# Generated by FakeRAM 2.0
VERSION 5.7 ;
BUSBITCHARS "[]" ;
PROPERTYDEFINITIONS
  MACRO width INTEGER ;
  MACRO depth INTEGER ;
  MACRO banks INTEGER ;
END PROPERTYDEFINITIONS
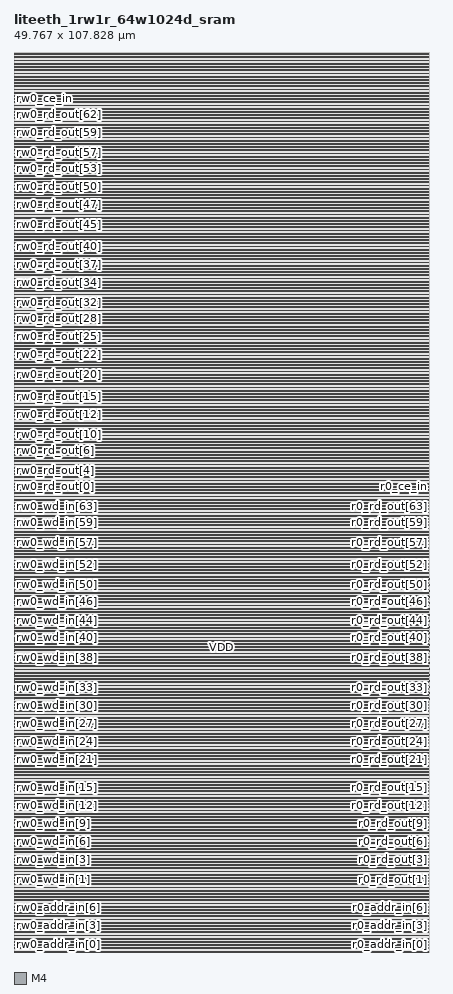
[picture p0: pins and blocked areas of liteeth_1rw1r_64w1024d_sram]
MACRO liteeth_1rw1r_64w1024d_sram
  PROPERTY width 64 ;
  PROPERTY depth 1024 ;
  PROPERTY banks 1 ;
  FOREIGN liteeth_1rw1r_64w1024d_sram 0 0 ;
  SYMMETRY X Y R90 ;
  SIZE 49.767 BY 107.828 ;
  CLASS BLOCK ;
  PIN r0_addr_in[0]
    DIRECTION INPUT ;
    USE SIGNAL ;
    SHAPE ABUTMENT ;
    PORT
      LAYER M4 ;
      RECT 49.743 0.048 49.767 0.072 ;
    END
  END r0_addr_in[0]
  PIN r0_addr_in[1]
    DIRECTION INPUT ;
    USE SIGNAL ;
    SHAPE ABUTMENT ;
    PORT
      LAYER M4 ;
      RECT 49.743 0.768 49.767 0.792 ;
    END
  END r0_addr_in[1]
  PIN r0_addr_in[2]
    DIRECTION INPUT ;
    USE SIGNAL ;
    SHAPE ABUTMENT ;
    PORT
      LAYER M4 ;
      RECT 49.743 1.488 49.767 1.512 ;
    END
  END r0_addr_in[2]
  PIN r0_addr_in[3]
    DIRECTION INPUT ;
    USE SIGNAL ;
    SHAPE ABUTMENT ;
    PORT
      LAYER M4 ;
      RECT 49.743 2.208 49.767 2.232 ;
    END
  END r0_addr_in[3]
  PIN r0_addr_in[4]
    DIRECTION INPUT ;
    USE SIGNAL ;
    SHAPE ABUTMENT ;
    PORT
      LAYER M4 ;
      RECT 49.743 2.928 49.767 2.952 ;
    END
  END r0_addr_in[4]
  PIN r0_addr_in[5]
    DIRECTION INPUT ;
    USE SIGNAL ;
    SHAPE ABUTMENT ;
    PORT
      LAYER M4 ;
      RECT 49.743 3.648 49.767 3.672 ;
    END
  END r0_addr_in[5]
  PIN r0_addr_in[6]
    DIRECTION INPUT ;
    USE SIGNAL ;
    SHAPE ABUTMENT ;
    PORT
      LAYER M4 ;
      RECT 49.743 4.368 49.767 4.392 ;
    END
  END r0_addr_in[6]
  PIN r0_addr_in[7]
    DIRECTION INPUT ;
    USE SIGNAL ;
    SHAPE ABUTMENT ;
    PORT
      LAYER M4 ;
      RECT 49.743 5.088 49.767 5.112 ;
    END
  END r0_addr_in[7]
  PIN r0_addr_in[8]
    DIRECTION INPUT ;
    USE SIGNAL ;
    SHAPE ABUTMENT ;
    PORT
      LAYER M4 ;
      RECT 49.743 5.808 49.767 5.832 ;
    END
  END r0_addr_in[8]
  PIN r0_addr_in[9]
    DIRECTION INPUT ;
    USE SIGNAL ;
    SHAPE ABUTMENT ;
    PORT
      LAYER M4 ;
      RECT 49.743 6.528 49.767 6.552 ;
    END
  END r0_addr_in[9]
  PIN r0_rd_out[0]
    DIRECTION OUTPUT ;
    USE SIGNAL ;
    SHAPE ABUTMENT ;
    PORT
      LAYER M4 ;
      RECT 49.743 7.968 49.767 7.992 ;
    END
  END r0_rd_out[0]
  PIN r0_rd_out[1]
    DIRECTION OUTPUT ;
    USE SIGNAL ;
    SHAPE ABUTMENT ;
    PORT
      LAYER M4 ;
      RECT 49.743 8.688 49.767 8.712 ;
    END
  END r0_rd_out[1]
  PIN r0_rd_out[2]
    DIRECTION OUTPUT ;
    USE SIGNAL ;
    SHAPE ABUTMENT ;
    PORT
      LAYER M4 ;
      RECT 49.743 9.408 49.767 9.432 ;
    END
  END r0_rd_out[2]
  PIN r0_rd_out[3]
    DIRECTION OUTPUT ;
    USE SIGNAL ;
    SHAPE ABUTMENT ;
    PORT
      LAYER M4 ;
      RECT 49.743 10.128 49.767 10.152 ;
    END
  END r0_rd_out[3]
  PIN r0_rd_out[4]
    DIRECTION OUTPUT ;
    USE SIGNAL ;
    SHAPE ABUTMENT ;
    PORT
      LAYER M4 ;
      RECT 49.743 10.848 49.767 10.872 ;
    END
  END r0_rd_out[4]
  PIN r0_rd_out[5]
    DIRECTION OUTPUT ;
    USE SIGNAL ;
    SHAPE ABUTMENT ;
    PORT
      LAYER M4 ;
      RECT 49.743 11.568 49.767 11.592 ;
    END
  END r0_rd_out[5]
  PIN r0_rd_out[6]
    DIRECTION OUTPUT ;
    USE SIGNAL ;
    SHAPE ABUTMENT ;
    PORT
      LAYER M4 ;
      RECT 49.743 12.288 49.767 12.312 ;
    END
  END r0_rd_out[6]
  PIN r0_rd_out[7]
    DIRECTION OUTPUT ;
    USE SIGNAL ;
    SHAPE ABUTMENT ;
    PORT
      LAYER M4 ;
      RECT 49.743 13.008 49.767 13.032 ;
    END
  END r0_rd_out[7]
  PIN r0_rd_out[8]
    DIRECTION OUTPUT ;
    USE SIGNAL ;
    SHAPE ABUTMENT ;
    PORT
      LAYER M4 ;
      RECT 49.743 13.728 49.767 13.752 ;
    END
  END r0_rd_out[8]
  PIN r0_rd_out[9]
    DIRECTION OUTPUT ;
    USE SIGNAL ;
    SHAPE ABUTMENT ;
    PORT
      LAYER M4 ;
      RECT 49.743 14.448 49.767 14.472 ;
    END
  END r0_rd_out[9]
  PIN r0_rd_out[10]
    DIRECTION OUTPUT ;
    USE SIGNAL ;
    SHAPE ABUTMENT ;
    PORT
      LAYER M4 ;
      RECT 49.743 15.168 49.767 15.192 ;
    END
  END r0_rd_out[10]
  PIN r0_rd_out[11]
    DIRECTION OUTPUT ;
    USE SIGNAL ;
    SHAPE ABUTMENT ;
    PORT
      LAYER M4 ;
      RECT 49.743 15.888 49.767 15.912 ;
    END
  END r0_rd_out[11]
  PIN r0_rd_out[12]
    DIRECTION OUTPUT ;
    USE SIGNAL ;
    SHAPE ABUTMENT ;
    PORT
      LAYER M4 ;
      RECT 49.743 16.608 49.767 16.632 ;
    END
  END r0_rd_out[12]
  PIN r0_rd_out[13]
    DIRECTION OUTPUT ;
    USE SIGNAL ;
    SHAPE ABUTMENT ;
    PORT
      LAYER M4 ;
      RECT 49.743 17.328 49.767 17.352 ;
    END
  END r0_rd_out[13]
  PIN r0_rd_out[14]
    DIRECTION OUTPUT ;
    USE SIGNAL ;
    SHAPE ABUTMENT ;
    PORT
      LAYER M4 ;
      RECT 49.743 18.048 49.767 18.072 ;
    END
  END r0_rd_out[14]
  PIN r0_rd_out[15]
    DIRECTION OUTPUT ;
    USE SIGNAL ;
    SHAPE ABUTMENT ;
    PORT
      LAYER M4 ;
      RECT 49.743 18.768 49.767 18.792 ;
    END
  END r0_rd_out[15]
  PIN r0_rd_out[16]
    DIRECTION OUTPUT ;
    USE SIGNAL ;
    SHAPE ABUTMENT ;
    PORT
      LAYER M4 ;
      RECT 49.743 19.488 49.767 19.512 ;
    END
  END r0_rd_out[16]
  PIN r0_rd_out[17]
    DIRECTION OUTPUT ;
    USE SIGNAL ;
    SHAPE ABUTMENT ;
    PORT
      LAYER M4 ;
      RECT 49.743 20.208 49.767 20.232 ;
    END
  END r0_rd_out[17]
  PIN r0_rd_out[18]
    DIRECTION OUTPUT ;
    USE SIGNAL ;
    SHAPE ABUTMENT ;
    PORT
      LAYER M4 ;
      RECT 49.743 20.928 49.767 20.952 ;
    END
  END r0_rd_out[18]
  PIN r0_rd_out[19]
    DIRECTION OUTPUT ;
    USE SIGNAL ;
    SHAPE ABUTMENT ;
    PORT
      LAYER M4 ;
      RECT 49.743 21.648 49.767 21.672 ;
    END
  END r0_rd_out[19]
  PIN r0_rd_out[20]
    DIRECTION OUTPUT ;
    USE SIGNAL ;
    SHAPE ABUTMENT ;
    PORT
      LAYER M4 ;
      RECT 49.743 22.368 49.767 22.392 ;
    END
  END r0_rd_out[20]
  PIN r0_rd_out[21]
    DIRECTION OUTPUT ;
    USE SIGNAL ;
    SHAPE ABUTMENT ;
    PORT
      LAYER M4 ;
      RECT 49.743 23.088 49.767 23.112 ;
    END
  END r0_rd_out[21]
  PIN r0_rd_out[22]
    DIRECTION OUTPUT ;
    USE SIGNAL ;
    SHAPE ABUTMENT ;
    PORT
      LAYER M4 ;
      RECT 49.743 23.808 49.767 23.832 ;
    END
  END r0_rd_out[22]
  PIN r0_rd_out[23]
    DIRECTION OUTPUT ;
    USE SIGNAL ;
    SHAPE ABUTMENT ;
    PORT
      LAYER M4 ;
      RECT 49.743 24.528 49.767 24.552 ;
    END
  END r0_rd_out[23]
  PIN r0_rd_out[24]
    DIRECTION OUTPUT ;
    USE SIGNAL ;
    SHAPE ABUTMENT ;
    PORT
      LAYER M4 ;
      RECT 49.743 25.248 49.767 25.272 ;
    END
  END r0_rd_out[24]
  PIN r0_rd_out[25]
    DIRECTION OUTPUT ;
    USE SIGNAL ;
    SHAPE ABUTMENT ;
    PORT
      LAYER M4 ;
      RECT 49.743 25.968 49.767 25.992 ;
    END
  END r0_rd_out[25]
  PIN r0_rd_out[26]
    DIRECTION OUTPUT ;
    USE SIGNAL ;
    SHAPE ABUTMENT ;
    PORT
      LAYER M4 ;
      RECT 49.743 26.688 49.767 26.712 ;
    END
  END r0_rd_out[26]
  PIN r0_rd_out[27]
    DIRECTION OUTPUT ;
    USE SIGNAL ;
    SHAPE ABUTMENT ;
    PORT
      LAYER M4 ;
      RECT 49.743 27.408 49.767 27.432 ;
    END
  END r0_rd_out[27]
  PIN r0_rd_out[28]
    DIRECTION OUTPUT ;
    USE SIGNAL ;
    SHAPE ABUTMENT ;
    PORT
      LAYER M4 ;
      RECT 49.743 28.128 49.767 28.152 ;
    END
  END r0_rd_out[28]
  PIN r0_rd_out[29]
    DIRECTION OUTPUT ;
    USE SIGNAL ;
    SHAPE ABUTMENT ;
    PORT
      LAYER M4 ;
      RECT 49.743 28.848 49.767 28.872 ;
    END
  END r0_rd_out[29]
  PIN r0_rd_out[30]
    DIRECTION OUTPUT ;
    USE SIGNAL ;
    SHAPE ABUTMENT ;
    PORT
      LAYER M4 ;
      RECT 49.743 29.568 49.767 29.592 ;
    END
  END r0_rd_out[30]
  PIN r0_rd_out[31]
    DIRECTION OUTPUT ;
    USE SIGNAL ;
    SHAPE ABUTMENT ;
    PORT
      LAYER M4 ;
      RECT 49.743 30.288 49.767 30.312 ;
    END
  END r0_rd_out[31]
  PIN r0_rd_out[32]
    DIRECTION OUTPUT ;
    USE SIGNAL ;
    SHAPE ABUTMENT ;
    PORT
      LAYER M4 ;
      RECT 49.743 31.008 49.767 31.032 ;
    END
  END r0_rd_out[32]
  PIN r0_rd_out[33]
    DIRECTION OUTPUT ;
    USE SIGNAL ;
    SHAPE ABUTMENT ;
    PORT
      LAYER M4 ;
      RECT 49.743 31.728 49.767 31.752 ;
    END
  END r0_rd_out[33]
  PIN r0_rd_out[34]
    DIRECTION OUTPUT ;
    USE SIGNAL ;
    SHAPE ABUTMENT ;
    PORT
      LAYER M4 ;
      RECT 49.743 32.448 49.767 32.472 ;
    END
  END r0_rd_out[34]
  PIN r0_rd_out[35]
    DIRECTION OUTPUT ;
    USE SIGNAL ;
    SHAPE ABUTMENT ;
    PORT
      LAYER M4 ;
      RECT 49.743 33.168 49.767 33.192 ;
    END
  END r0_rd_out[35]
  PIN r0_rd_out[36]
    DIRECTION OUTPUT ;
    USE SIGNAL ;
    SHAPE ABUTMENT ;
    PORT
      LAYER M4 ;
      RECT 49.743 33.888 49.767 33.912 ;
    END
  END r0_rd_out[36]
  PIN r0_rd_out[37]
    DIRECTION OUTPUT ;
    USE SIGNAL ;
    SHAPE ABUTMENT ;
    PORT
      LAYER M4 ;
      RECT 49.743 34.608 49.767 34.632 ;
    END
  END r0_rd_out[37]
  PIN r0_rd_out[38]
    DIRECTION OUTPUT ;
    USE SIGNAL ;
    SHAPE ABUTMENT ;
    PORT
      LAYER M4 ;
      RECT 49.743 35.328 49.767 35.352 ;
    END
  END r0_rd_out[38]
  PIN r0_rd_out[39]
    DIRECTION OUTPUT ;
    USE SIGNAL ;
    SHAPE ABUTMENT ;
    PORT
      LAYER M4 ;
      RECT 49.743 36.048 49.767 36.072 ;
    END
  END r0_rd_out[39]
  PIN r0_rd_out[40]
    DIRECTION OUTPUT ;
    USE SIGNAL ;
    SHAPE ABUTMENT ;
    PORT
      LAYER M4 ;
      RECT 49.743 36.768 49.767 36.792 ;
    END
  END r0_rd_out[40]
  PIN r0_rd_out[41]
    DIRECTION OUTPUT ;
    USE SIGNAL ;
    SHAPE ABUTMENT ;
    PORT
      LAYER M4 ;
      RECT 49.743 37.488 49.767 37.512 ;
    END
  END r0_rd_out[41]
  PIN r0_rd_out[42]
    DIRECTION OUTPUT ;
    USE SIGNAL ;
    SHAPE ABUTMENT ;
    PORT
      LAYER M4 ;
      RECT 49.743 38.208 49.767 38.232 ;
    END
  END r0_rd_out[42]
  PIN r0_rd_out[43]
    DIRECTION OUTPUT ;
    USE SIGNAL ;
    SHAPE ABUTMENT ;
    PORT
      LAYER M4 ;
      RECT 49.743 38.928 49.767 38.952 ;
    END
  END r0_rd_out[43]
  PIN r0_rd_out[44]
    DIRECTION OUTPUT ;
    USE SIGNAL ;
    SHAPE ABUTMENT ;
    PORT
      LAYER M4 ;
      RECT 49.743 39.648 49.767 39.672 ;
    END
  END r0_rd_out[44]
  PIN r0_rd_out[45]
    DIRECTION OUTPUT ;
    USE SIGNAL ;
    SHAPE ABUTMENT ;
    PORT
      LAYER M4 ;
      RECT 49.743 40.368 49.767 40.392 ;
    END
  END r0_rd_out[45]
  PIN r0_rd_out[46]
    DIRECTION OUTPUT ;
    USE SIGNAL ;
    SHAPE ABUTMENT ;
    PORT
      LAYER M4 ;
      RECT 49.743 41.088 49.767 41.112 ;
    END
  END r0_rd_out[46]
  PIN r0_rd_out[47]
    DIRECTION OUTPUT ;
    USE SIGNAL ;
    SHAPE ABUTMENT ;
    PORT
      LAYER M4 ;
      RECT 49.743 41.808 49.767 41.832 ;
    END
  END r0_rd_out[47]
  PIN r0_rd_out[48]
    DIRECTION OUTPUT ;
    USE SIGNAL ;
    SHAPE ABUTMENT ;
    PORT
      LAYER M4 ;
      RECT 49.743 42.528 49.767 42.552 ;
    END
  END r0_rd_out[48]
  PIN r0_rd_out[49]
    DIRECTION OUTPUT ;
    USE SIGNAL ;
    SHAPE ABUTMENT ;
    PORT
      LAYER M4 ;
      RECT 49.743 43.248 49.767 43.272 ;
    END
  END r0_rd_out[49]
  PIN r0_rd_out[50]
    DIRECTION OUTPUT ;
    USE SIGNAL ;
    SHAPE ABUTMENT ;
    PORT
      LAYER M4 ;
      RECT 49.743 43.968 49.767 43.992 ;
    END
  END r0_rd_out[50]
  PIN r0_rd_out[51]
    DIRECTION OUTPUT ;
    USE SIGNAL ;
    SHAPE ABUTMENT ;
    PORT
      LAYER M4 ;
      RECT 49.743 44.688 49.767 44.712 ;
    END
  END r0_rd_out[51]
  PIN r0_rd_out[52]
    DIRECTION OUTPUT ;
    USE SIGNAL ;
    SHAPE ABUTMENT ;
    PORT
      LAYER M4 ;
      RECT 49.743 45.408 49.767 45.432 ;
    END
  END r0_rd_out[52]
  PIN r0_rd_out[53]
    DIRECTION OUTPUT ;
    USE SIGNAL ;
    SHAPE ABUTMENT ;
    PORT
      LAYER M4 ;
      RECT 49.743 46.128 49.767 46.152 ;
    END
  END r0_rd_out[53]
  PIN r0_rd_out[54]
    DIRECTION OUTPUT ;
    USE SIGNAL ;
    SHAPE ABUTMENT ;
    PORT
      LAYER M4 ;
      RECT 49.743 46.848 49.767 46.872 ;
    END
  END r0_rd_out[54]
  PIN r0_rd_out[55]
    DIRECTION OUTPUT ;
    USE SIGNAL ;
    SHAPE ABUTMENT ;
    PORT
      LAYER M4 ;
      RECT 49.743 47.568 49.767 47.592 ;
    END
  END r0_rd_out[55]
  PIN r0_rd_out[56]
    DIRECTION OUTPUT ;
    USE SIGNAL ;
    SHAPE ABUTMENT ;
    PORT
      LAYER M4 ;
      RECT 49.743 48.288 49.767 48.312 ;
    END
  END r0_rd_out[56]
  PIN r0_rd_out[57]
    DIRECTION OUTPUT ;
    USE SIGNAL ;
    SHAPE ABUTMENT ;
    PORT
      LAYER M4 ;
      RECT 49.743 49.008 49.767 49.032 ;
    END
  END r0_rd_out[57]
  PIN r0_rd_out[58]
    DIRECTION OUTPUT ;
    USE SIGNAL ;
    SHAPE ABUTMENT ;
    PORT
      LAYER M4 ;
      RECT 49.743 49.728 49.767 49.752 ;
    END
  END r0_rd_out[58]
  PIN r0_rd_out[59]
    DIRECTION OUTPUT ;
    USE SIGNAL ;
    SHAPE ABUTMENT ;
    PORT
      LAYER M4 ;
      RECT 49.743 50.448 49.767 50.472 ;
    END
  END r0_rd_out[59]
  PIN r0_rd_out[60]
    DIRECTION OUTPUT ;
    USE SIGNAL ;
    SHAPE ABUTMENT ;
    PORT
      LAYER M4 ;
      RECT 49.743 51.168 49.767 51.192 ;
    END
  END r0_rd_out[60]
  PIN r0_rd_out[61]
    DIRECTION OUTPUT ;
    USE SIGNAL ;
    SHAPE ABUTMENT ;
    PORT
      LAYER M4 ;
      RECT 49.743 51.888 49.767 51.912 ;
    END
  END r0_rd_out[61]
  PIN r0_rd_out[62]
    DIRECTION OUTPUT ;
    USE SIGNAL ;
    SHAPE ABUTMENT ;
    PORT
      LAYER M4 ;
      RECT 49.743 52.608 49.767 52.632 ;
    END
  END r0_rd_out[62]
  PIN r0_rd_out[63]
    DIRECTION OUTPUT ;
    USE SIGNAL ;
    SHAPE ABUTMENT ;
    PORT
      LAYER M4 ;
      RECT 49.743 53.328 49.767 53.352 ;
    END
  END r0_rd_out[63]
  PIN r0_ce_in
    DIRECTION INPUT ;
    USE SIGNAL ;
    SHAPE ABUTMENT ;
    PORT
      LAYER M4 ;
      RECT 49.743 54.768 49.767 54.792 ;
    END
  END r0_ce_in
  PIN r0_clk
    DIRECTION INPUT ;
    USE SIGNAL ;
    SHAPE ABUTMENT ;
    PORT
      LAYER M4 ;
      RECT 49.743 55.488 49.767 55.512 ;
    END
  END r0_clk
  PIN rw0_addr_in[0]
    DIRECTION INPUT ;
    USE SIGNAL ;
    SHAPE ABUTMENT ;
    PORT
      LAYER M4 ;
      RECT 0.000 0.048 0.024 0.072 ;
    END
  END rw0_addr_in[0]
  PIN rw0_addr_in[1]
    DIRECTION INPUT ;
    USE SIGNAL ;
    SHAPE ABUTMENT ;
    PORT
      LAYER M4 ;
      RECT 0.000 0.768 0.024 0.792 ;
    END
  END rw0_addr_in[1]
  PIN rw0_addr_in[2]
    DIRECTION INPUT ;
    USE SIGNAL ;
    SHAPE ABUTMENT ;
    PORT
      LAYER M4 ;
      RECT 0.000 1.488 0.024 1.512 ;
    END
  END rw0_addr_in[2]
  PIN rw0_addr_in[3]
    DIRECTION INPUT ;
    USE SIGNAL ;
    SHAPE ABUTMENT ;
    PORT
      LAYER M4 ;
      RECT 0.000 2.208 0.024 2.232 ;
    END
  END rw0_addr_in[3]
  PIN rw0_addr_in[4]
    DIRECTION INPUT ;
    USE SIGNAL ;
    SHAPE ABUTMENT ;
    PORT
      LAYER M4 ;
      RECT 0.000 2.928 0.024 2.952 ;
    END
  END rw0_addr_in[4]
  PIN rw0_addr_in[5]
    DIRECTION INPUT ;
    USE SIGNAL ;
    SHAPE ABUTMENT ;
    PORT
      LAYER M4 ;
      RECT 0.000 3.648 0.024 3.672 ;
    END
  END rw0_addr_in[5]
  PIN rw0_addr_in[6]
    DIRECTION INPUT ;
    USE SIGNAL ;
    SHAPE ABUTMENT ;
    PORT
      LAYER M4 ;
      RECT 0.000 4.368 0.024 4.392 ;
    END
  END rw0_addr_in[6]
  PIN rw0_addr_in[7]
    DIRECTION INPUT ;
    USE SIGNAL ;
    SHAPE ABUTMENT ;
    PORT
      LAYER M4 ;
      RECT 0.000 5.088 0.024 5.112 ;
    END
  END rw0_addr_in[7]
  PIN rw0_addr_in[8]
    DIRECTION INPUT ;
    USE SIGNAL ;
    SHAPE ABUTMENT ;
    PORT
      LAYER M4 ;
      RECT 0.000 5.808 0.024 5.832 ;
    END
  END rw0_addr_in[8]
  PIN rw0_addr_in[9]
    DIRECTION INPUT ;
    USE SIGNAL ;
    SHAPE ABUTMENT ;
    PORT
      LAYER M4 ;
      RECT 0.000 6.528 0.024 6.552 ;
    END
  END rw0_addr_in[9]
  PIN rw0_wd_in[0]
    DIRECTION INPUT ;
    USE SIGNAL ;
    SHAPE ABUTMENT ;
    PORT
      LAYER M4 ;
      RECT 0.000 7.968 0.024 7.992 ;
    END
  END rw0_wd_in[0]
  PIN rw0_wd_in[1]
    DIRECTION INPUT ;
    USE SIGNAL ;
    SHAPE ABUTMENT ;
    PORT
      LAYER M4 ;
      RECT 0.000 8.688 0.024 8.712 ;
    END
  END rw0_wd_in[1]
  PIN rw0_wd_in[2]
    DIRECTION INPUT ;
    USE SIGNAL ;
    SHAPE ABUTMENT ;
    PORT
      LAYER M4 ;
      RECT 0.000 9.408 0.024 9.432 ;
    END
  END rw0_wd_in[2]
  PIN rw0_wd_in[3]
    DIRECTION INPUT ;
    USE SIGNAL ;
    SHAPE ABUTMENT ;
    PORT
      LAYER M4 ;
      RECT 0.000 10.128 0.024 10.152 ;
    END
  END rw0_wd_in[3]
  PIN rw0_wd_in[4]
    DIRECTION INPUT ;
    USE SIGNAL ;
    SHAPE ABUTMENT ;
    PORT
      LAYER M4 ;
      RECT 0.000 10.848 0.024 10.872 ;
    END
  END rw0_wd_in[4]
  PIN rw0_wd_in[5]
    DIRECTION INPUT ;
    USE SIGNAL ;
    SHAPE ABUTMENT ;
    PORT
      LAYER M4 ;
      RECT 0.000 11.568 0.024 11.592 ;
    END
  END rw0_wd_in[5]
  PIN rw0_wd_in[6]
    DIRECTION INPUT ;
    USE SIGNAL ;
    SHAPE ABUTMENT ;
    PORT
      LAYER M4 ;
      RECT 0.000 12.288 0.024 12.312 ;
    END
  END rw0_wd_in[6]
  PIN rw0_wd_in[7]
    DIRECTION INPUT ;
    USE SIGNAL ;
    SHAPE ABUTMENT ;
    PORT
      LAYER M4 ;
      RECT 0.000 13.008 0.024 13.032 ;
    END
  END rw0_wd_in[7]
  PIN rw0_wd_in[8]
    DIRECTION INPUT ;
    USE SIGNAL ;
    SHAPE ABUTMENT ;
    PORT
      LAYER M4 ;
      RECT 0.000 13.728 0.024 13.752 ;
    END
  END rw0_wd_in[8]
  PIN rw0_wd_in[9]
    DIRECTION INPUT ;
    USE SIGNAL ;
    SHAPE ABUTMENT ;
    PORT
      LAYER M4 ;
      RECT 0.000 14.448 0.024 14.472 ;
    END
  END rw0_wd_in[9]
  PIN rw0_wd_in[10]
    DIRECTION INPUT ;
    USE SIGNAL ;
    SHAPE ABUTMENT ;
    PORT
      LAYER M4 ;
      RECT 0.000 15.168 0.024 15.192 ;
    END
  END rw0_wd_in[10]
  PIN rw0_wd_in[11]
    DIRECTION INPUT ;
    USE SIGNAL ;
    SHAPE ABUTMENT ;
    PORT
      LAYER M4 ;
      RECT 0.000 15.888 0.024 15.912 ;
    END
  END rw0_wd_in[11]
  PIN rw0_wd_in[12]
    DIRECTION INPUT ;
    USE SIGNAL ;
    SHAPE ABUTMENT ;
    PORT
      LAYER M4 ;
      RECT 0.000 16.608 0.024 16.632 ;
    END
  END rw0_wd_in[12]
  PIN rw0_wd_in[13]
    DIRECTION INPUT ;
    USE SIGNAL ;
    SHAPE ABUTMENT ;
    PORT
      LAYER M4 ;
      RECT 0.000 17.328 0.024 17.352 ;
    END
  END rw0_wd_in[13]
  PIN rw0_wd_in[14]
    DIRECTION INPUT ;
    USE SIGNAL ;
    SHAPE ABUTMENT ;
    PORT
      LAYER M4 ;
      RECT 0.000 18.048 0.024 18.072 ;
    END
  END rw0_wd_in[14]
  PIN rw0_wd_in[15]
    DIRECTION INPUT ;
    USE SIGNAL ;
    SHAPE ABUTMENT ;
    PORT
      LAYER M4 ;
      RECT 0.000 18.768 0.024 18.792 ;
    END
  END rw0_wd_in[15]
  PIN rw0_wd_in[16]
    DIRECTION INPUT ;
    USE SIGNAL ;
    SHAPE ABUTMENT ;
    PORT
      LAYER M4 ;
      RECT 0.000 19.488 0.024 19.512 ;
    END
  END rw0_wd_in[16]
  PIN rw0_wd_in[17]
    DIRECTION INPUT ;
    USE SIGNAL ;
    SHAPE ABUTMENT ;
    PORT
      LAYER M4 ;
      RECT 0.000 20.208 0.024 20.232 ;
    END
  END rw0_wd_in[17]
  PIN rw0_wd_in[18]
    DIRECTION INPUT ;
    USE SIGNAL ;
    SHAPE ABUTMENT ;
    PORT
      LAYER M4 ;
      RECT 0.000 20.928 0.024 20.952 ;
    END
  END rw0_wd_in[18]
  PIN rw0_wd_in[19]
    DIRECTION INPUT ;
    USE SIGNAL ;
    SHAPE ABUTMENT ;
    PORT
      LAYER M4 ;
      RECT 0.000 21.648 0.024 21.672 ;
    END
  END rw0_wd_in[19]
  PIN rw0_wd_in[20]
    DIRECTION INPUT ;
    USE SIGNAL ;
    SHAPE ABUTMENT ;
    PORT
      LAYER M4 ;
      RECT 0.000 22.368 0.024 22.392 ;
    END
  END rw0_wd_in[20]
  PIN rw0_wd_in[21]
    DIRECTION INPUT ;
    USE SIGNAL ;
    SHAPE ABUTMENT ;
    PORT
      LAYER M4 ;
      RECT 0.000 23.088 0.024 23.112 ;
    END
  END rw0_wd_in[21]
  PIN rw0_wd_in[22]
    DIRECTION INPUT ;
    USE SIGNAL ;
    SHAPE ABUTMENT ;
    PORT
      LAYER M4 ;
      RECT 0.000 23.808 0.024 23.832 ;
    END
  END rw0_wd_in[22]
  PIN rw0_wd_in[23]
    DIRECTION INPUT ;
    USE SIGNAL ;
    SHAPE ABUTMENT ;
    PORT
      LAYER M4 ;
      RECT 0.000 24.528 0.024 24.552 ;
    END
  END rw0_wd_in[23]
  PIN rw0_wd_in[24]
    DIRECTION INPUT ;
    USE SIGNAL ;
    SHAPE ABUTMENT ;
    PORT
      LAYER M4 ;
      RECT 0.000 25.248 0.024 25.272 ;
    END
  END rw0_wd_in[24]
  PIN rw0_wd_in[25]
    DIRECTION INPUT ;
    USE SIGNAL ;
    SHAPE ABUTMENT ;
    PORT
      LAYER M4 ;
      RECT 0.000 25.968 0.024 25.992 ;
    END
  END rw0_wd_in[25]
  PIN rw0_wd_in[26]
    DIRECTION INPUT ;
    USE SIGNAL ;
    SHAPE ABUTMENT ;
    PORT
      LAYER M4 ;
      RECT 0.000 26.688 0.024 26.712 ;
    END
  END rw0_wd_in[26]
  PIN rw0_wd_in[27]
    DIRECTION INPUT ;
    USE SIGNAL ;
    SHAPE ABUTMENT ;
    PORT
      LAYER M4 ;
      RECT 0.000 27.408 0.024 27.432 ;
    END
  END rw0_wd_in[27]
  PIN rw0_wd_in[28]
    DIRECTION INPUT ;
    USE SIGNAL ;
    SHAPE ABUTMENT ;
    PORT
      LAYER M4 ;
      RECT 0.000 28.128 0.024 28.152 ;
    END
  END rw0_wd_in[28]
  PIN rw0_wd_in[29]
    DIRECTION INPUT ;
    USE SIGNAL ;
    SHAPE ABUTMENT ;
    PORT
      LAYER M4 ;
      RECT 0.000 28.848 0.024 28.872 ;
    END
  END rw0_wd_in[29]
  PIN rw0_wd_in[30]
    DIRECTION INPUT ;
    USE SIGNAL ;
    SHAPE ABUTMENT ;
    PORT
      LAYER M4 ;
      RECT 0.000 29.568 0.024 29.592 ;
    END
  END rw0_wd_in[30]
  PIN rw0_wd_in[31]
    DIRECTION INPUT ;
    USE SIGNAL ;
    SHAPE ABUTMENT ;
    PORT
      LAYER M4 ;
      RECT 0.000 30.288 0.024 30.312 ;
    END
  END rw0_wd_in[31]
  PIN rw0_wd_in[32]
    DIRECTION INPUT ;
    USE SIGNAL ;
    SHAPE ABUTMENT ;
    PORT
      LAYER M4 ;
      RECT 0.000 31.008 0.024 31.032 ;
    END
  END rw0_wd_in[32]
  PIN rw0_wd_in[33]
    DIRECTION INPUT ;
    USE SIGNAL ;
    SHAPE ABUTMENT ;
    PORT
      LAYER M4 ;
      RECT 0.000 31.728 0.024 31.752 ;
    END
  END rw0_wd_in[33]
  PIN rw0_wd_in[34]
    DIRECTION INPUT ;
    USE SIGNAL ;
    SHAPE ABUTMENT ;
    PORT
      LAYER M4 ;
      RECT 0.000 32.448 0.024 32.472 ;
    END
  END rw0_wd_in[34]
  PIN rw0_wd_in[35]
    DIRECTION INPUT ;
    USE SIGNAL ;
    SHAPE ABUTMENT ;
    PORT
      LAYER M4 ;
      RECT 0.000 33.168 0.024 33.192 ;
    END
  END rw0_wd_in[35]
  PIN rw0_wd_in[36]
    DIRECTION INPUT ;
    USE SIGNAL ;
    SHAPE ABUTMENT ;
    PORT
      LAYER M4 ;
      RECT 0.000 33.888 0.024 33.912 ;
    END
  END rw0_wd_in[36]
  PIN rw0_wd_in[37]
    DIRECTION INPUT ;
    USE SIGNAL ;
    SHAPE ABUTMENT ;
    PORT
      LAYER M4 ;
      RECT 0.000 34.608 0.024 34.632 ;
    END
  END rw0_wd_in[37]
  PIN rw0_wd_in[38]
    DIRECTION INPUT ;
    USE SIGNAL ;
    SHAPE ABUTMENT ;
    PORT
      LAYER M4 ;
      RECT 0.000 35.328 0.024 35.352 ;
    END
  END rw0_wd_in[38]
  PIN rw0_wd_in[39]
    DIRECTION INPUT ;
    USE SIGNAL ;
    SHAPE ABUTMENT ;
    PORT
      LAYER M4 ;
      RECT 0.000 36.048 0.024 36.072 ;
    END
  END rw0_wd_in[39]
  PIN rw0_wd_in[40]
    DIRECTION INPUT ;
    USE SIGNAL ;
    SHAPE ABUTMENT ;
    PORT
      LAYER M4 ;
      RECT 0.000 36.768 0.024 36.792 ;
    END
  END rw0_wd_in[40]
  PIN rw0_wd_in[41]
    DIRECTION INPUT ;
    USE SIGNAL ;
    SHAPE ABUTMENT ;
    PORT
      LAYER M4 ;
      RECT 0.000 37.488 0.024 37.512 ;
    END
  END rw0_wd_in[41]
  PIN rw0_wd_in[42]
    DIRECTION INPUT ;
    USE SIGNAL ;
    SHAPE ABUTMENT ;
    PORT
      LAYER M4 ;
      RECT 0.000 38.208 0.024 38.232 ;
    END
  END rw0_wd_in[42]
  PIN rw0_wd_in[43]
    DIRECTION INPUT ;
    USE SIGNAL ;
    SHAPE ABUTMENT ;
    PORT
      LAYER M4 ;
      RECT 0.000 38.928 0.024 38.952 ;
    END
  END rw0_wd_in[43]
  PIN rw0_wd_in[44]
    DIRECTION INPUT ;
    USE SIGNAL ;
    SHAPE ABUTMENT ;
    PORT
      LAYER M4 ;
      RECT 0.000 39.648 0.024 39.672 ;
    END
  END rw0_wd_in[44]
  PIN rw0_wd_in[45]
    DIRECTION INPUT ;
    USE SIGNAL ;
    SHAPE ABUTMENT ;
    PORT
      LAYER M4 ;
      RECT 0.000 40.368 0.024 40.392 ;
    END
  END rw0_wd_in[45]
  PIN rw0_wd_in[46]
    DIRECTION INPUT ;
    USE SIGNAL ;
    SHAPE ABUTMENT ;
    PORT
      LAYER M4 ;
      RECT 0.000 41.088 0.024 41.112 ;
    END
  END rw0_wd_in[46]
  PIN rw0_wd_in[47]
    DIRECTION INPUT ;
    USE SIGNAL ;
    SHAPE ABUTMENT ;
    PORT
      LAYER M4 ;
      RECT 0.000 41.808 0.024 41.832 ;
    END
  END rw0_wd_in[47]
  PIN rw0_wd_in[48]
    DIRECTION INPUT ;
    USE SIGNAL ;
    SHAPE ABUTMENT ;
    PORT
      LAYER M4 ;
      RECT 0.000 42.528 0.024 42.552 ;
    END
  END rw0_wd_in[48]
  PIN rw0_wd_in[49]
    DIRECTION INPUT ;
    USE SIGNAL ;
    SHAPE ABUTMENT ;
    PORT
      LAYER M4 ;
      RECT 0.000 43.248 0.024 43.272 ;
    END
  END rw0_wd_in[49]
  PIN rw0_wd_in[50]
    DIRECTION INPUT ;
    USE SIGNAL ;
    SHAPE ABUTMENT ;
    PORT
      LAYER M4 ;
      RECT 0.000 43.968 0.024 43.992 ;
    END
  END rw0_wd_in[50]
  PIN rw0_wd_in[51]
    DIRECTION INPUT ;
    USE SIGNAL ;
    SHAPE ABUTMENT ;
    PORT
      LAYER M4 ;
      RECT 0.000 44.688 0.024 44.712 ;
    END
  END rw0_wd_in[51]
  PIN rw0_wd_in[52]
    DIRECTION INPUT ;
    USE SIGNAL ;
    SHAPE ABUTMENT ;
    PORT
      LAYER M4 ;
      RECT 0.000 45.408 0.024 45.432 ;
    END
  END rw0_wd_in[52]
  PIN rw0_wd_in[53]
    DIRECTION INPUT ;
    USE SIGNAL ;
    SHAPE ABUTMENT ;
    PORT
      LAYER M4 ;
      RECT 0.000 46.128 0.024 46.152 ;
    END
  END rw0_wd_in[53]
  PIN rw0_wd_in[54]
    DIRECTION INPUT ;
    USE SIGNAL ;
    SHAPE ABUTMENT ;
    PORT
      LAYER M4 ;
      RECT 0.000 46.848 0.024 46.872 ;
    END
  END rw0_wd_in[54]
  PIN rw0_wd_in[55]
    DIRECTION INPUT ;
    USE SIGNAL ;
    SHAPE ABUTMENT ;
    PORT
      LAYER M4 ;
      RECT 0.000 47.568 0.024 47.592 ;
    END
  END rw0_wd_in[55]
  PIN rw0_wd_in[56]
    DIRECTION INPUT ;
    USE SIGNAL ;
    SHAPE ABUTMENT ;
    PORT
      LAYER M4 ;
      RECT 0.000 48.288 0.024 48.312 ;
    END
  END rw0_wd_in[56]
  PIN rw0_wd_in[57]
    DIRECTION INPUT ;
    USE SIGNAL ;
    SHAPE ABUTMENT ;
    PORT
      LAYER M4 ;
      RECT 0.000 49.008 0.024 49.032 ;
    END
  END rw0_wd_in[57]
  PIN rw0_wd_in[58]
    DIRECTION INPUT ;
    USE SIGNAL ;
    SHAPE ABUTMENT ;
    PORT
      LAYER M4 ;
      RECT 0.000 49.728 0.024 49.752 ;
    END
  END rw0_wd_in[58]
  PIN rw0_wd_in[59]
    DIRECTION INPUT ;
    USE SIGNAL ;
    SHAPE ABUTMENT ;
    PORT
      LAYER M4 ;
      RECT 0.000 50.448 0.024 50.472 ;
    END
  END rw0_wd_in[59]
  PIN rw0_wd_in[60]
    DIRECTION INPUT ;
    USE SIGNAL ;
    SHAPE ABUTMENT ;
    PORT
      LAYER M4 ;
      RECT 0.000 51.168 0.024 51.192 ;
    END
  END rw0_wd_in[60]
  PIN rw0_wd_in[61]
    DIRECTION INPUT ;
    USE SIGNAL ;
    SHAPE ABUTMENT ;
    PORT
      LAYER M4 ;
      RECT 0.000 51.888 0.024 51.912 ;
    END
  END rw0_wd_in[61]
  PIN rw0_wd_in[62]
    DIRECTION INPUT ;
    USE SIGNAL ;
    SHAPE ABUTMENT ;
    PORT
      LAYER M4 ;
      RECT 0.000 52.608 0.024 52.632 ;
    END
  END rw0_wd_in[62]
  PIN rw0_wd_in[63]
    DIRECTION INPUT ;
    USE SIGNAL ;
    SHAPE ABUTMENT ;
    PORT
      LAYER M4 ;
      RECT 0.000 53.328 0.024 53.352 ;
    END
  END rw0_wd_in[63]
  PIN rw0_rd_out[0]
    DIRECTION OUTPUT ;
    USE SIGNAL ;
    SHAPE ABUTMENT ;
    PORT
      LAYER M4 ;
      RECT 0.000 54.768 0.024 54.792 ;
    END
  END rw0_rd_out[0]
  PIN rw0_rd_out[1]
    DIRECTION OUTPUT ;
    USE SIGNAL ;
    SHAPE ABUTMENT ;
    PORT
      LAYER M4 ;
      RECT 0.000 55.488 0.024 55.512 ;
    END
  END rw0_rd_out[1]
  PIN rw0_rd_out[2]
    DIRECTION OUTPUT ;
    USE SIGNAL ;
    SHAPE ABUTMENT ;
    PORT
      LAYER M4 ;
      RECT 0.000 56.208 0.024 56.232 ;
    END
  END rw0_rd_out[2]
  PIN rw0_rd_out[3]
    DIRECTION OUTPUT ;
    USE SIGNAL ;
    SHAPE ABUTMENT ;
    PORT
      LAYER M4 ;
      RECT 0.000 56.928 0.024 56.952 ;
    END
  END rw0_rd_out[3]
  PIN rw0_rd_out[4]
    DIRECTION OUTPUT ;
    USE SIGNAL ;
    SHAPE ABUTMENT ;
    PORT
      LAYER M4 ;
      RECT 0.000 57.648 0.024 57.672 ;
    END
  END rw0_rd_out[4]
  PIN rw0_rd_out[5]
    DIRECTION OUTPUT ;
    USE SIGNAL ;
    SHAPE ABUTMENT ;
    PORT
      LAYER M4 ;
      RECT 0.000 58.368 0.024 58.392 ;
    END
  END rw0_rd_out[5]
  PIN rw0_rd_out[6]
    DIRECTION OUTPUT ;
    USE SIGNAL ;
    SHAPE ABUTMENT ;
    PORT
      LAYER M4 ;
      RECT 0.000 59.088 0.024 59.112 ;
    END
  END rw0_rd_out[6]
  PIN rw0_rd_out[7]
    DIRECTION OUTPUT ;
    USE SIGNAL ;
    SHAPE ABUTMENT ;
    PORT
      LAYER M4 ;
      RECT 0.000 59.808 0.024 59.832 ;
    END
  END rw0_rd_out[7]
  PIN rw0_rd_out[8]
    DIRECTION OUTPUT ;
    USE SIGNAL ;
    SHAPE ABUTMENT ;
    PORT
      LAYER M4 ;
      RECT 0.000 60.528 0.024 60.552 ;
    END
  END rw0_rd_out[8]
  PIN rw0_rd_out[9]
    DIRECTION OUTPUT ;
    USE SIGNAL ;
    SHAPE ABUTMENT ;
    PORT
      LAYER M4 ;
      RECT 0.000 61.248 0.024 61.272 ;
    END
  END rw0_rd_out[9]
  PIN rw0_rd_out[10]
    DIRECTION OUTPUT ;
    USE SIGNAL ;
    SHAPE ABUTMENT ;
    PORT
      LAYER M4 ;
      RECT 0.000 61.968 0.024 61.992 ;
    END
  END rw0_rd_out[10]
  PIN rw0_rd_out[11]
    DIRECTION OUTPUT ;
    USE SIGNAL ;
    SHAPE ABUTMENT ;
    PORT
      LAYER M4 ;
      RECT 0.000 62.688 0.024 62.712 ;
    END
  END rw0_rd_out[11]
  PIN rw0_rd_out[12]
    DIRECTION OUTPUT ;
    USE SIGNAL ;
    SHAPE ABUTMENT ;
    PORT
      LAYER M4 ;
      RECT 0.000 63.408 0.024 63.432 ;
    END
  END rw0_rd_out[12]
  PIN rw0_rd_out[13]
    DIRECTION OUTPUT ;
    USE SIGNAL ;
    SHAPE ABUTMENT ;
    PORT
      LAYER M4 ;
      RECT 0.000 64.128 0.024 64.152 ;
    END
  END rw0_rd_out[13]
  PIN rw0_rd_out[14]
    DIRECTION OUTPUT ;
    USE SIGNAL ;
    SHAPE ABUTMENT ;
    PORT
      LAYER M4 ;
      RECT 0.000 64.848 0.024 64.872 ;
    END
  END rw0_rd_out[14]
  PIN rw0_rd_out[15]
    DIRECTION OUTPUT ;
    USE SIGNAL ;
    SHAPE ABUTMENT ;
    PORT
      LAYER M4 ;
      RECT 0.000 65.568 0.024 65.592 ;
    END
  END rw0_rd_out[15]
  PIN rw0_rd_out[16]
    DIRECTION OUTPUT ;
    USE SIGNAL ;
    SHAPE ABUTMENT ;
    PORT
      LAYER M4 ;
      RECT 0.000 66.288 0.024 66.312 ;
    END
  END rw0_rd_out[16]
  PIN rw0_rd_out[17]
    DIRECTION OUTPUT ;
    USE SIGNAL ;
    SHAPE ABUTMENT ;
    PORT
      LAYER M4 ;
      RECT 0.000 67.008 0.024 67.032 ;
    END
  END rw0_rd_out[17]
  PIN rw0_rd_out[18]
    DIRECTION OUTPUT ;
    USE SIGNAL ;
    SHAPE ABUTMENT ;
    PORT
      LAYER M4 ;
      RECT 0.000 67.728 0.024 67.752 ;
    END
  END rw0_rd_out[18]
  PIN rw0_rd_out[19]
    DIRECTION OUTPUT ;
    USE SIGNAL ;
    SHAPE ABUTMENT ;
    PORT
      LAYER M4 ;
      RECT 0.000 68.448 0.024 68.472 ;
    END
  END rw0_rd_out[19]
  PIN rw0_rd_out[20]
    DIRECTION OUTPUT ;
    USE SIGNAL ;
    SHAPE ABUTMENT ;
    PORT
      LAYER M4 ;
      RECT 0.000 69.168 0.024 69.192 ;
    END
  END rw0_rd_out[20]
  PIN rw0_rd_out[21]
    DIRECTION OUTPUT ;
    USE SIGNAL ;
    SHAPE ABUTMENT ;
    PORT
      LAYER M4 ;
      RECT 0.000 69.888 0.024 69.912 ;
    END
  END rw0_rd_out[21]
  PIN rw0_rd_out[22]
    DIRECTION OUTPUT ;
    USE SIGNAL ;
    SHAPE ABUTMENT ;
    PORT
      LAYER M4 ;
      RECT 0.000 70.608 0.024 70.632 ;
    END
  END rw0_rd_out[22]
  PIN rw0_rd_out[23]
    DIRECTION OUTPUT ;
    USE SIGNAL ;
    SHAPE ABUTMENT ;
    PORT
      LAYER M4 ;
      RECT 0.000 71.328 0.024 71.352 ;
    END
  END rw0_rd_out[23]
  PIN rw0_rd_out[24]
    DIRECTION OUTPUT ;
    USE SIGNAL ;
    SHAPE ABUTMENT ;
    PORT
      LAYER M4 ;
      RECT 0.000 72.048 0.024 72.072 ;
    END
  END rw0_rd_out[24]
  PIN rw0_rd_out[25]
    DIRECTION OUTPUT ;
    USE SIGNAL ;
    SHAPE ABUTMENT ;
    PORT
      LAYER M4 ;
      RECT 0.000 72.768 0.024 72.792 ;
    END
  END rw0_rd_out[25]
  PIN rw0_rd_out[26]
    DIRECTION OUTPUT ;
    USE SIGNAL ;
    SHAPE ABUTMENT ;
    PORT
      LAYER M4 ;
      RECT 0.000 73.488 0.024 73.512 ;
    END
  END rw0_rd_out[26]
  PIN rw0_rd_out[27]
    DIRECTION OUTPUT ;
    USE SIGNAL ;
    SHAPE ABUTMENT ;
    PORT
      LAYER M4 ;
      RECT 0.000 74.208 0.024 74.232 ;
    END
  END rw0_rd_out[27]
  PIN rw0_rd_out[28]
    DIRECTION OUTPUT ;
    USE SIGNAL ;
    SHAPE ABUTMENT ;
    PORT
      LAYER M4 ;
      RECT 0.000 74.928 0.024 74.952 ;
    END
  END rw0_rd_out[28]
  PIN rw0_rd_out[29]
    DIRECTION OUTPUT ;
    USE SIGNAL ;
    SHAPE ABUTMENT ;
    PORT
      LAYER M4 ;
      RECT 0.000 75.648 0.024 75.672 ;
    END
  END rw0_rd_out[29]
  PIN rw0_rd_out[30]
    DIRECTION OUTPUT ;
    USE SIGNAL ;
    SHAPE ABUTMENT ;
    PORT
      LAYER M4 ;
      RECT 0.000 76.368 0.024 76.392 ;
    END
  END rw0_rd_out[30]
  PIN rw0_rd_out[31]
    DIRECTION OUTPUT ;
    USE SIGNAL ;
    SHAPE ABUTMENT ;
    PORT
      LAYER M4 ;
      RECT 0.000 77.088 0.024 77.112 ;
    END
  END rw0_rd_out[31]
  PIN rw0_rd_out[32]
    DIRECTION OUTPUT ;
    USE SIGNAL ;
    SHAPE ABUTMENT ;
    PORT
      LAYER M4 ;
      RECT 0.000 77.808 0.024 77.832 ;
    END
  END rw0_rd_out[32]
  PIN rw0_rd_out[33]
    DIRECTION OUTPUT ;
    USE SIGNAL ;
    SHAPE ABUTMENT ;
    PORT
      LAYER M4 ;
      RECT 0.000 78.528 0.024 78.552 ;
    END
  END rw0_rd_out[33]
  PIN rw0_rd_out[34]
    DIRECTION OUTPUT ;
    USE SIGNAL ;
    SHAPE ABUTMENT ;
    PORT
      LAYER M4 ;
      RECT 0.000 79.248 0.024 79.272 ;
    END
  END rw0_rd_out[34]
  PIN rw0_rd_out[35]
    DIRECTION OUTPUT ;
    USE SIGNAL ;
    SHAPE ABUTMENT ;
    PORT
      LAYER M4 ;
      RECT 0.000 79.968 0.024 79.992 ;
    END
  END rw0_rd_out[35]
  PIN rw0_rd_out[36]
    DIRECTION OUTPUT ;
    USE SIGNAL ;
    SHAPE ABUTMENT ;
    PORT
      LAYER M4 ;
      RECT 0.000 80.688 0.024 80.712 ;
    END
  END rw0_rd_out[36]
  PIN rw0_rd_out[37]
    DIRECTION OUTPUT ;
    USE SIGNAL ;
    SHAPE ABUTMENT ;
    PORT
      LAYER M4 ;
      RECT 0.000 81.408 0.024 81.432 ;
    END
  END rw0_rd_out[37]
  PIN rw0_rd_out[38]
    DIRECTION OUTPUT ;
    USE SIGNAL ;
    SHAPE ABUTMENT ;
    PORT
      LAYER M4 ;
      RECT 0.000 82.128 0.024 82.152 ;
    END
  END rw0_rd_out[38]
  PIN rw0_rd_out[39]
    DIRECTION OUTPUT ;
    USE SIGNAL ;
    SHAPE ABUTMENT ;
    PORT
      LAYER M4 ;
      RECT 0.000 82.848 0.024 82.872 ;
    END
  END rw0_rd_out[39]
  PIN rw0_rd_out[40]
    DIRECTION OUTPUT ;
    USE SIGNAL ;
    SHAPE ABUTMENT ;
    PORT
      LAYER M4 ;
      RECT 0.000 83.568 0.024 83.592 ;
    END
  END rw0_rd_out[40]
  PIN rw0_rd_out[41]
    DIRECTION OUTPUT ;
    USE SIGNAL ;
    SHAPE ABUTMENT ;
    PORT
      LAYER M4 ;
      RECT 0.000 84.288 0.024 84.312 ;
    END
  END rw0_rd_out[41]
  PIN rw0_rd_out[42]
    DIRECTION OUTPUT ;
    USE SIGNAL ;
    SHAPE ABUTMENT ;
    PORT
      LAYER M4 ;
      RECT 0.000 85.008 0.024 85.032 ;
    END
  END rw0_rd_out[42]
  PIN rw0_rd_out[43]
    DIRECTION OUTPUT ;
    USE SIGNAL ;
    SHAPE ABUTMENT ;
    PORT
      LAYER M4 ;
      RECT 0.000 85.728 0.024 85.752 ;
    END
  END rw0_rd_out[43]
  PIN rw0_rd_out[44]
    DIRECTION OUTPUT ;
    USE SIGNAL ;
    SHAPE ABUTMENT ;
    PORT
      LAYER M4 ;
      RECT 0.000 86.448 0.024 86.472 ;
    END
  END rw0_rd_out[44]
  PIN rw0_rd_out[45]
    DIRECTION OUTPUT ;
    USE SIGNAL ;
    SHAPE ABUTMENT ;
    PORT
      LAYER M4 ;
      RECT 0.000 87.168 0.024 87.192 ;
    END
  END rw0_rd_out[45]
  PIN rw0_rd_out[46]
    DIRECTION OUTPUT ;
    USE SIGNAL ;
    SHAPE ABUTMENT ;
    PORT
      LAYER M4 ;
      RECT 0.000 87.888 0.024 87.912 ;
    END
  END rw0_rd_out[46]
  PIN rw0_rd_out[47]
    DIRECTION OUTPUT ;
    USE SIGNAL ;
    SHAPE ABUTMENT ;
    PORT
      LAYER M4 ;
      RECT 0.000 88.608 0.024 88.632 ;
    END
  END rw0_rd_out[47]
  PIN rw0_rd_out[48]
    DIRECTION OUTPUT ;
    USE SIGNAL ;
    SHAPE ABUTMENT ;
    PORT
      LAYER M4 ;
      RECT 0.000 89.328 0.024 89.352 ;
    END
  END rw0_rd_out[48]
  PIN rw0_rd_out[49]
    DIRECTION OUTPUT ;
    USE SIGNAL ;
    SHAPE ABUTMENT ;
    PORT
      LAYER M4 ;
      RECT 0.000 90.048 0.024 90.072 ;
    END
  END rw0_rd_out[49]
  PIN rw0_rd_out[50]
    DIRECTION OUTPUT ;
    USE SIGNAL ;
    SHAPE ABUTMENT ;
    PORT
      LAYER M4 ;
      RECT 0.000 90.768 0.024 90.792 ;
    END
  END rw0_rd_out[50]
  PIN rw0_rd_out[51]
    DIRECTION OUTPUT ;
    USE SIGNAL ;
    SHAPE ABUTMENT ;
    PORT
      LAYER M4 ;
      RECT 0.000 91.488 0.024 91.512 ;
    END
  END rw0_rd_out[51]
  PIN rw0_rd_out[52]
    DIRECTION OUTPUT ;
    USE SIGNAL ;
    SHAPE ABUTMENT ;
    PORT
      LAYER M4 ;
      RECT 0.000 92.208 0.024 92.232 ;
    END
  END rw0_rd_out[52]
  PIN rw0_rd_out[53]
    DIRECTION OUTPUT ;
    USE SIGNAL ;
    SHAPE ABUTMENT ;
    PORT
      LAYER M4 ;
      RECT 0.000 92.928 0.024 92.952 ;
    END
  END rw0_rd_out[53]
  PIN rw0_rd_out[54]
    DIRECTION OUTPUT ;
    USE SIGNAL ;
    SHAPE ABUTMENT ;
    PORT
      LAYER M4 ;
      RECT 0.000 93.648 0.024 93.672 ;
    END
  END rw0_rd_out[54]
  PIN rw0_rd_out[55]
    DIRECTION OUTPUT ;
    USE SIGNAL ;
    SHAPE ABUTMENT ;
    PORT
      LAYER M4 ;
      RECT 0.000 94.368 0.024 94.392 ;
    END
  END rw0_rd_out[55]
  PIN rw0_rd_out[56]
    DIRECTION OUTPUT ;
    USE SIGNAL ;
    SHAPE ABUTMENT ;
    PORT
      LAYER M4 ;
      RECT 0.000 95.088 0.024 95.112 ;
    END
  END rw0_rd_out[56]
  PIN rw0_rd_out[57]
    DIRECTION OUTPUT ;
    USE SIGNAL ;
    SHAPE ABUTMENT ;
    PORT
      LAYER M4 ;
      RECT 0.000 95.808 0.024 95.832 ;
    END
  END rw0_rd_out[57]
  PIN rw0_rd_out[58]
    DIRECTION OUTPUT ;
    USE SIGNAL ;
    SHAPE ABUTMENT ;
    PORT
      LAYER M4 ;
      RECT 0.000 96.528 0.024 96.552 ;
    END
  END rw0_rd_out[58]
  PIN rw0_rd_out[59]
    DIRECTION OUTPUT ;
    USE SIGNAL ;
    SHAPE ABUTMENT ;
    PORT
      LAYER M4 ;
      RECT 0.000 97.248 0.024 97.272 ;
    END
  END rw0_rd_out[59]
  PIN rw0_rd_out[60]
    DIRECTION OUTPUT ;
    USE SIGNAL ;
    SHAPE ABUTMENT ;
    PORT
      LAYER M4 ;
      RECT 0.000 97.968 0.024 97.992 ;
    END
  END rw0_rd_out[60]
  PIN rw0_rd_out[61]
    DIRECTION OUTPUT ;
    USE SIGNAL ;
    SHAPE ABUTMENT ;
    PORT
      LAYER M4 ;
      RECT 0.000 98.688 0.024 98.712 ;
    END
  END rw0_rd_out[61]
  PIN rw0_rd_out[62]
    DIRECTION OUTPUT ;
    USE SIGNAL ;
    SHAPE ABUTMENT ;
    PORT
      LAYER M4 ;
      RECT 0.000 99.408 0.024 99.432 ;
    END
  END rw0_rd_out[62]
  PIN rw0_rd_out[63]
    DIRECTION OUTPUT ;
    USE SIGNAL ;
    SHAPE ABUTMENT ;
    PORT
      LAYER M4 ;
      RECT 0.000 100.128 0.024 100.152 ;
    END
  END rw0_rd_out[63]
  PIN rw0_we_in
    DIRECTION INPUT ;
    USE SIGNAL ;
    SHAPE ABUTMENT ;
    PORT
      LAYER M4 ;
      RECT 0.000 101.568 0.024 101.592 ;
    END
  END rw0_we_in
  PIN rw0_ce_in
    DIRECTION INPUT ;
    USE SIGNAL ;
    SHAPE ABUTMENT ;
    PORT
      LAYER M4 ;
      RECT 0.000 102.288 0.024 102.312 ;
    END
  END rw0_ce_in
  PIN rw0_clk
    DIRECTION INPUT ;
    USE SIGNAL ;
    SHAPE ABUTMENT ;
    PORT
      LAYER M4 ;
      RECT 0.000 103.008 0.024 103.032 ;
    END
  END rw0_clk
  PIN VSS
    DIRECTION INOUT ;
    USE GROUND ;
    PORT
      LAYER M4 ;
      RECT 0.048 0.000 49.719 0.096 ;
      RECT 0.048 0.768 49.719 0.864 ;
      RECT 0.048 1.536 49.719 1.632 ;
      RECT 0.048 2.304 49.719 2.400 ;
      RECT 0.048 3.072 49.719 3.168 ;
      RECT 0.048 3.840 49.719 3.936 ;
      RECT 0.048 4.608 49.719 4.704 ;
      RECT 0.048 5.376 49.719 5.472 ;
      RECT 0.048 6.144 49.719 6.240 ;
      RECT 0.048 6.912 49.719 7.008 ;
      RECT 0.048 7.680 49.719 7.776 ;
      RECT 0.048 8.448 49.719 8.544 ;
      RECT 0.048 9.216 49.719 9.312 ;
      RECT 0.048 9.984 49.719 10.080 ;
      RECT 0.048 10.752 49.719 10.848 ;
      RECT 0.048 11.520 49.719 11.616 ;
      RECT 0.048 12.288 49.719 12.384 ;
      RECT 0.048 13.056 49.719 13.152 ;
      RECT 0.048 13.824 49.719 13.920 ;
      RECT 0.048 14.592 49.719 14.688 ;
      RECT 0.048 15.360 49.719 15.456 ;
      RECT 0.048 16.128 49.719 16.224 ;
      RECT 0.048 16.896 49.719 16.992 ;
      RECT 0.048 17.664 49.719 17.760 ;
      RECT 0.048 18.432 49.719 18.528 ;
      RECT 0.048 19.200 49.719 19.296 ;
      RECT 0.048 19.968 49.719 20.064 ;
      RECT 0.048 20.736 49.719 20.832 ;
      RECT 0.048 21.504 49.719 21.600 ;
      RECT 0.048 22.272 49.719 22.368 ;
      RECT 0.048 23.040 49.719 23.136 ;
      RECT 0.048 23.808 49.719 23.904 ;
      RECT 0.048 24.576 49.719 24.672 ;
      RECT 0.048 25.344 49.719 25.440 ;
      RECT 0.048 26.112 49.719 26.208 ;
      RECT 0.048 26.880 49.719 26.976 ;
      RECT 0.048 27.648 49.719 27.744 ;
      RECT 0.048 28.416 49.719 28.512 ;
      RECT 0.048 29.184 49.719 29.280 ;
      RECT 0.048 29.952 49.719 30.048 ;
      RECT 0.048 30.720 49.719 30.816 ;
      RECT 0.048 31.488 49.719 31.584 ;
      RECT 0.048 32.256 49.719 32.352 ;
      RECT 0.048 33.024 49.719 33.120 ;
      RECT 0.048 33.792 49.719 33.888 ;
      RECT 0.048 34.560 49.719 34.656 ;
      RECT 0.048 35.328 49.719 35.424 ;
      RECT 0.048 36.096 49.719 36.192 ;
      RECT 0.048 36.864 49.719 36.960 ;
      RECT 0.048 37.632 49.719 37.728 ;
      RECT 0.048 38.400 49.719 38.496 ;
      RECT 0.048 39.168 49.719 39.264 ;
      RECT 0.048 39.936 49.719 40.032 ;
      RECT 0.048 40.704 49.719 40.800 ;
      RECT 0.048 41.472 49.719 41.568 ;
      RECT 0.048 42.240 49.719 42.336 ;
      RECT 0.048 43.008 49.719 43.104 ;
      RECT 0.048 43.776 49.719 43.872 ;
      RECT 0.048 44.544 49.719 44.640 ;
      RECT 0.048 45.312 49.719 45.408 ;
      RECT 0.048 46.080 49.719 46.176 ;
      RECT 0.048 46.848 49.719 46.944 ;
      RECT 0.048 47.616 49.719 47.712 ;
      RECT 0.048 48.384 49.719 48.480 ;
      RECT 0.048 49.152 49.719 49.248 ;
      RECT 0.048 49.920 49.719 50.016 ;
      RECT 0.048 50.688 49.719 50.784 ;
      RECT 0.048 51.456 49.719 51.552 ;
      RECT 0.048 52.224 49.719 52.320 ;
      RECT 0.048 52.992 49.719 53.088 ;
      RECT 0.048 53.760 49.719 53.856 ;
      RECT 0.048 54.528 49.719 54.624 ;
      RECT 0.048 55.296 49.719 55.392 ;
      RECT 0.048 56.064 49.719 56.160 ;
      RECT 0.048 56.832 49.719 56.928 ;
      RECT 0.048 57.600 49.719 57.696 ;
      RECT 0.048 58.368 49.719 58.464 ;
      RECT 0.048 59.136 49.719 59.232 ;
      RECT 0.048 59.904 49.719 60.000 ;
      RECT 0.048 60.672 49.719 60.768 ;
      RECT 0.048 61.440 49.719 61.536 ;
      RECT 0.048 62.208 49.719 62.304 ;
      RECT 0.048 62.976 49.719 63.072 ;
      RECT 0.048 63.744 49.719 63.840 ;
      RECT 0.048 64.512 49.719 64.608 ;
      RECT 0.048 65.280 49.719 65.376 ;
      RECT 0.048 66.048 49.719 66.144 ;
      RECT 0.048 66.816 49.719 66.912 ;
      RECT 0.048 67.584 49.719 67.680 ;
      RECT 0.048 68.352 49.719 68.448 ;
      RECT 0.048 69.120 49.719 69.216 ;
      RECT 0.048 69.888 49.719 69.984 ;
      RECT 0.048 70.656 49.719 70.752 ;
      RECT 0.048 71.424 49.719 71.520 ;
      RECT 0.048 72.192 49.719 72.288 ;
      RECT 0.048 72.960 49.719 73.056 ;
      RECT 0.048 73.728 49.719 73.824 ;
      RECT 0.048 74.496 49.719 74.592 ;
      RECT 0.048 75.264 49.719 75.360 ;
      RECT 0.048 76.032 49.719 76.128 ;
      RECT 0.048 76.800 49.719 76.896 ;
      RECT 0.048 77.568 49.719 77.664 ;
      RECT 0.048 78.336 49.719 78.432 ;
      RECT 0.048 79.104 49.719 79.200 ;
      RECT 0.048 79.872 49.719 79.968 ;
      RECT 0.048 80.640 49.719 80.736 ;
      RECT 0.048 81.408 49.719 81.504 ;
      RECT 0.048 82.176 49.719 82.272 ;
      RECT 0.048 82.944 49.719 83.040 ;
      RECT 0.048 83.712 49.719 83.808 ;
      RECT 0.048 84.480 49.719 84.576 ;
      RECT 0.048 85.248 49.719 85.344 ;
      RECT 0.048 86.016 49.719 86.112 ;
      RECT 0.048 86.784 49.719 86.880 ;
      RECT 0.048 87.552 49.719 87.648 ;
      RECT 0.048 88.320 49.719 88.416 ;
      RECT 0.048 89.088 49.719 89.184 ;
      RECT 0.048 89.856 49.719 89.952 ;
      RECT 0.048 90.624 49.719 90.720 ;
      RECT 0.048 91.392 49.719 91.488 ;
      RECT 0.048 92.160 49.719 92.256 ;
      RECT 0.048 92.928 49.719 93.024 ;
      RECT 0.048 93.696 49.719 93.792 ;
      RECT 0.048 94.464 49.719 94.560 ;
      RECT 0.048 95.232 49.719 95.328 ;
      RECT 0.048 96.000 49.719 96.096 ;
      RECT 0.048 96.768 49.719 96.864 ;
      RECT 0.048 97.536 49.719 97.632 ;
      RECT 0.048 98.304 49.719 98.400 ;
      RECT 0.048 99.072 49.719 99.168 ;
      RECT 0.048 99.840 49.719 99.936 ;
      RECT 0.048 100.608 49.719 100.704 ;
      RECT 0.048 101.376 49.719 101.472 ;
      RECT 0.048 102.144 49.719 102.240 ;
      RECT 0.048 102.912 49.719 103.008 ;
      RECT 0.048 103.680 49.719 103.776 ;
      RECT 0.048 104.448 49.719 104.544 ;
      RECT 0.048 105.216 49.719 105.312 ;
      RECT 0.048 105.984 49.719 106.080 ;
      RECT 0.048 106.752 49.719 106.848 ;
      RECT 0.048 107.520 49.719 107.616 ;
    END
  END VSS
  PIN VDD
    DIRECTION INOUT ;
    USE POWER ;
    PORT
      LAYER M4 ;
      RECT 0.048 0.384 49.719 0.480 ;
      RECT 0.048 1.152 49.719 1.248 ;
      RECT 0.048 1.920 49.719 2.016 ;
      RECT 0.048 2.688 49.719 2.784 ;
      RECT 0.048 3.456 49.719 3.552 ;
      RECT 0.048 4.224 49.719 4.320 ;
      RECT 0.048 4.992 49.719 5.088 ;
      RECT 0.048 5.760 49.719 5.856 ;
      RECT 0.048 6.528 49.719 6.624 ;
      RECT 0.048 7.296 49.719 7.392 ;
      RECT 0.048 8.064 49.719 8.160 ;
      RECT 0.048 8.832 49.719 8.928 ;
      RECT 0.048 9.600 49.719 9.696 ;
      RECT 0.048 10.368 49.719 10.464 ;
      RECT 0.048 11.136 49.719 11.232 ;
      RECT 0.048 11.904 49.719 12.000 ;
      RECT 0.048 12.672 49.719 12.768 ;
      RECT 0.048 13.440 49.719 13.536 ;
      RECT 0.048 14.208 49.719 14.304 ;
      RECT 0.048 14.976 49.719 15.072 ;
      RECT 0.048 15.744 49.719 15.840 ;
      RECT 0.048 16.512 49.719 16.608 ;
      RECT 0.048 17.280 49.719 17.376 ;
      RECT 0.048 18.048 49.719 18.144 ;
      RECT 0.048 18.816 49.719 18.912 ;
      RECT 0.048 19.584 49.719 19.680 ;
      RECT 0.048 20.352 49.719 20.448 ;
      RECT 0.048 21.120 49.719 21.216 ;
      RECT 0.048 21.888 49.719 21.984 ;
      RECT 0.048 22.656 49.719 22.752 ;
      RECT 0.048 23.424 49.719 23.520 ;
      RECT 0.048 24.192 49.719 24.288 ;
      RECT 0.048 24.960 49.719 25.056 ;
      RECT 0.048 25.728 49.719 25.824 ;
      RECT 0.048 26.496 49.719 26.592 ;
      RECT 0.048 27.264 49.719 27.360 ;
      RECT 0.048 28.032 49.719 28.128 ;
      RECT 0.048 28.800 49.719 28.896 ;
      RECT 0.048 29.568 49.719 29.664 ;
      RECT 0.048 30.336 49.719 30.432 ;
      RECT 0.048 31.104 49.719 31.200 ;
      RECT 0.048 31.872 49.719 31.968 ;
      RECT 0.048 32.640 49.719 32.736 ;
      RECT 0.048 33.408 49.719 33.504 ;
      RECT 0.048 34.176 49.719 34.272 ;
      RECT 0.048 34.944 49.719 35.040 ;
      RECT 0.048 35.712 49.719 35.808 ;
      RECT 0.048 36.480 49.719 36.576 ;
      RECT 0.048 37.248 49.719 37.344 ;
      RECT 0.048 38.016 49.719 38.112 ;
      RECT 0.048 38.784 49.719 38.880 ;
      RECT 0.048 39.552 49.719 39.648 ;
      RECT 0.048 40.320 49.719 40.416 ;
      RECT 0.048 41.088 49.719 41.184 ;
      RECT 0.048 41.856 49.719 41.952 ;
      RECT 0.048 42.624 49.719 42.720 ;
      RECT 0.048 43.392 49.719 43.488 ;
      RECT 0.048 44.160 49.719 44.256 ;
      RECT 0.048 44.928 49.719 45.024 ;
      RECT 0.048 45.696 49.719 45.792 ;
      RECT 0.048 46.464 49.719 46.560 ;
      RECT 0.048 47.232 49.719 47.328 ;
      RECT 0.048 48.000 49.719 48.096 ;
      RECT 0.048 48.768 49.719 48.864 ;
      RECT 0.048 49.536 49.719 49.632 ;
      RECT 0.048 50.304 49.719 50.400 ;
      RECT 0.048 51.072 49.719 51.168 ;
      RECT 0.048 51.840 49.719 51.936 ;
      RECT 0.048 52.608 49.719 52.704 ;
      RECT 0.048 53.376 49.719 53.472 ;
      RECT 0.048 54.144 49.719 54.240 ;
      RECT 0.048 54.912 49.719 55.008 ;
      RECT 0.048 55.680 49.719 55.776 ;
      RECT 0.048 56.448 49.719 56.544 ;
      RECT 0.048 57.216 49.719 57.312 ;
      RECT 0.048 57.984 49.719 58.080 ;
      RECT 0.048 58.752 49.719 58.848 ;
      RECT 0.048 59.520 49.719 59.616 ;
      RECT 0.048 60.288 49.719 60.384 ;
      RECT 0.048 61.056 49.719 61.152 ;
      RECT 0.048 61.824 49.719 61.920 ;
      RECT 0.048 62.592 49.719 62.688 ;
      RECT 0.048 63.360 49.719 63.456 ;
      RECT 0.048 64.128 49.719 64.224 ;
      RECT 0.048 64.896 49.719 64.992 ;
      RECT 0.048 65.664 49.719 65.760 ;
      RECT 0.048 66.432 49.719 66.528 ;
      RECT 0.048 67.200 49.719 67.296 ;
      RECT 0.048 67.968 49.719 68.064 ;
      RECT 0.048 68.736 49.719 68.832 ;
      RECT 0.048 69.504 49.719 69.600 ;
      RECT 0.048 70.272 49.719 70.368 ;
      RECT 0.048 71.040 49.719 71.136 ;
      RECT 0.048 71.808 49.719 71.904 ;
      RECT 0.048 72.576 49.719 72.672 ;
      RECT 0.048 73.344 49.719 73.440 ;
      RECT 0.048 74.112 49.719 74.208 ;
      RECT 0.048 74.880 49.719 74.976 ;
      RECT 0.048 75.648 49.719 75.744 ;
      RECT 0.048 76.416 49.719 76.512 ;
      RECT 0.048 77.184 49.719 77.280 ;
      RECT 0.048 77.952 49.719 78.048 ;
      RECT 0.048 78.720 49.719 78.816 ;
      RECT 0.048 79.488 49.719 79.584 ;
      RECT 0.048 80.256 49.719 80.352 ;
      RECT 0.048 81.024 49.719 81.120 ;
      RECT 0.048 81.792 49.719 81.888 ;
      RECT 0.048 82.560 49.719 82.656 ;
      RECT 0.048 83.328 49.719 83.424 ;
      RECT 0.048 84.096 49.719 84.192 ;
      RECT 0.048 84.864 49.719 84.960 ;
      RECT 0.048 85.632 49.719 85.728 ;
      RECT 0.048 86.400 49.719 86.496 ;
      RECT 0.048 87.168 49.719 87.264 ;
      RECT 0.048 87.936 49.719 88.032 ;
      RECT 0.048 88.704 49.719 88.800 ;
      RECT 0.048 89.472 49.719 89.568 ;
      RECT 0.048 90.240 49.719 90.336 ;
      RECT 0.048 91.008 49.719 91.104 ;
      RECT 0.048 91.776 49.719 91.872 ;
      RECT 0.048 92.544 49.719 92.640 ;
      RECT 0.048 93.312 49.719 93.408 ;
      RECT 0.048 94.080 49.719 94.176 ;
      RECT 0.048 94.848 49.719 94.944 ;
      RECT 0.048 95.616 49.719 95.712 ;
      RECT 0.048 96.384 49.719 96.480 ;
      RECT 0.048 97.152 49.719 97.248 ;
      RECT 0.048 97.920 49.719 98.016 ;
      RECT 0.048 98.688 49.719 98.784 ;
      RECT 0.048 99.456 49.719 99.552 ;
      RECT 0.048 100.224 49.719 100.320 ;
      RECT 0.048 100.992 49.719 101.088 ;
      RECT 0.048 101.760 49.719 101.856 ;
      RECT 0.048 102.528 49.719 102.624 ;
      RECT 0.048 103.296 49.719 103.392 ;
      RECT 0.048 104.064 49.719 104.160 ;
      RECT 0.048 104.832 49.719 104.928 ;
      RECT 0.048 105.600 49.719 105.696 ;
      RECT 0.048 106.368 49.719 106.464 ;
      RECT 0.048 107.136 49.719 107.232 ;
    END
  END VDD
  OBS
    LAYER M1 ;
    RECT 0 0 49.767 107.828 ;
    LAYER M2 ;
    RECT 0 0 49.767 107.828 ;
    LAYER M3 ;
    RECT 0 0 49.767 107.828 ;
    LAYER M4 ;
    RECT 0 0 49.767 107.828 ;
  END
END liteeth_1rw1r_64w1024d_sram

END LIBRARY
